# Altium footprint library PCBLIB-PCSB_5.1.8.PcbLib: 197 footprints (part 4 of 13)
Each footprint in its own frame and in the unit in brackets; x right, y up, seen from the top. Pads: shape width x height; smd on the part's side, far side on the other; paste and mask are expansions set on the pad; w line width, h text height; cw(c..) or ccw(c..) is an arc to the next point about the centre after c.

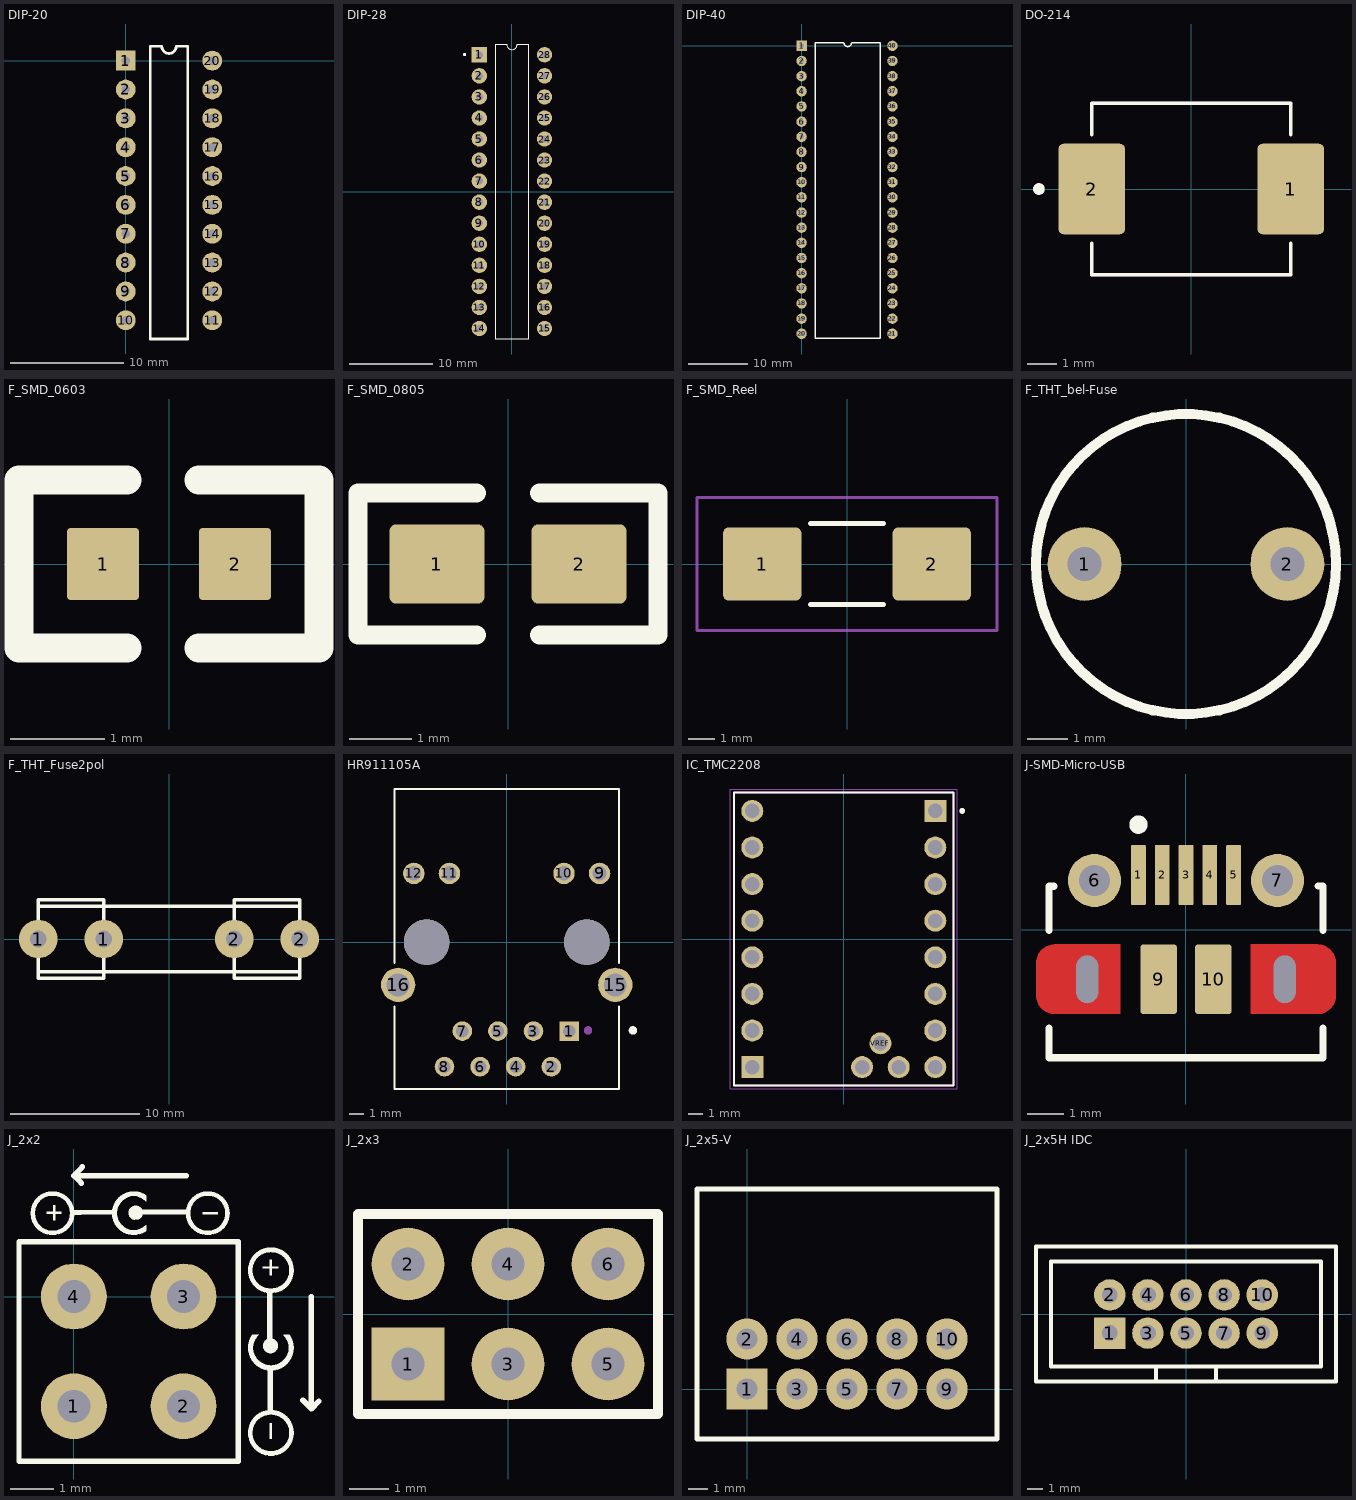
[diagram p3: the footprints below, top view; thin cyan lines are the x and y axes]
## DIP-20 [mm] "LB-2024-04-17"
pads (20):
  rect 1.75x1.75 hole 0.75: 1(0,0)
  round 1.75 hole 0.75: 2(0,-2.54) 3(0,-5.08) 4(0,-7.62) 5(0,-10.16) 6(0,-12.7) 7(0,-15.24) 8(0,-17.78) 9(0,-20.32) 10(0,-22.86) 11(7.62,-22.86) 12(7.62,-20.32) 13(7.62,-17.78) 14(7.62,-15.24) 15(7.62,-12.7) 16(7.62,-10.16) 17(7.62,-7.62) 18(7.62,-5.08) 19(7.62,-2.54) 20(7.62,0)
Top Overlay:
  lines w0.254: 2.159,-24.511 2.159,1.27 3.175,1.27 ccw(c3.81,1.27) 4.445,1.27 5.461,1.27 5.461,-24.511 2.159,-24.511

## DIP-28 [mm] "LB-2024-04-17"
pads (28):
  rect 1.85x1.85 hole 0.85: 1(-3.935,16.51)
  round 1.85 hole 0.85: 2(-3.935,13.97) 3(-3.935,11.43) 4(-3.935,8.89) 5(-3.935,6.35) 6(-3.935,3.81) 7(-3.935,1.27) 8(-3.935,-1.27) 9(-3.935,-3.81) 10(-3.935,-6.35) 11(-3.935,-8.89) 12(-3.935,-11.43) 13(-3.935,-13.97) 14(-3.935,-16.51) 15(3.935,-16.51) 16(3.935,-13.97) 17(3.935,-11.43) 18(3.935,-8.89) 19(3.935,-6.35) 20(3.935,-3.81) 21(3.935,-1.27) 22(3.935,1.27) 23(3.935,3.81) 24(3.935,6.35) 25(3.935,8.89) 26(3.935,11.43) 27(3.935,13.97) 28(3.935,16.51)
Top Overlay:
  circle w0.2: c-5.714,16.544 r0.1
  lines w0.14: -0.66,17.78 -1,17.78 -2,17.78 -2,-17.78 2,-17.78 2,17.78 ; -0.635,17.78 ccw(c0,17.78) 0.635,17.78 ; 0.642,17.78 1.642,17.78 1.981,17.78
Mechanical 13:
  circle w0.2: c-5.714,16.544 r0.1

## DIP-40 [mm] "LB-2024-04-17"
pads (40):
  rect 1.75x1.75 hole 0.75: 1(0,0)
  round 1.75 hole 0.75: 2(0,-2.54) 3(0,-5.08) 4(0,-7.62) 5(0,-10.16) 6(0,-12.7) 7(0,-15.24) 8(0,-17.78) 9(0,-20.32) 10(0,-22.86) 11(0,-25.4) 12(0,-27.94) 13(0,-30.48) 14(0,-33.02) 15(0,-35.56) 16(0,-38.1) 17(0,-40.64) 18(0,-43.18) 19(0,-45.72) 20(0,-48.26) 21(15.24,-48.26) 22(15.24,-45.72) 23(15.24,-43.18) 24(15.24,-40.64) 25(15.24,-38.1) 26(15.24,-35.56) 27(15.24,-33.02) 28(15.24,-30.48) 29(15.24,-27.94) 30(15.24,-25.4) 31(15.24,-22.86) 32(15.24,-20.32) 33(15.24,-17.78) 34(15.24,-15.24) 35(15.24,-12.7) 36(15.24,-10.16) 37(15.24,-7.62) 38(15.24,-5.08) 39(15.24,-2.54) 40(15.24,0)
Top Overlay:
  lines w0.254: 2.286,-49.022 13.208,-49.022 13.208,0.508 8.382,0.508 cw(c7.747,0.508) 7.112,0.508 2.286,0.508 2.286,-49.022

## DO-214 [mm] "LB-2024-09-01"
pads (2):
  rrect15% 2.29x3.12 smd paste-0.02 mask+0.05: 1(3.43,0) 2(-3.43,0)
Top Overlay:
  circle w0.2: c-5.25,0 r0.1
  lines w0.127: -3.427,-1.88 -3.427,-2.953 3.427,-2.953 3.427,-1.88 ; -3.427,1.88 -3.427,2.953 3.427,2.953 3.427,1.88
Mechanical 13:
  circle w0.2: c-5.25,0 r0.1
  lines w0.127: -3.427,-2.953 3.427,-2.953 ; -3.427,2.953 3.427,2.953

## F_SMD_0603 [mil] "LB-2024-04-17"
pads (2):
  rrect10% 30x30 smd paste-0.79 mask+1.97: 1(-27.5,0) 2(27.5,0)
Top Overlay:
  lines w12: -17.5,-35 -62.5,-35 -62.5,35 -17.5,35 ; 12.5,-35 62.5,-35 62.5,35 12.5,35

## F_SMD_0805 [mil] "LB-2024-04-17"
pads (2):
  rrect15% 60x50 smd paste-0.79 mask+1.97: 1(-45,0) 2(45,0)
Top Overlay:
  lines w12: -20,-45 -95,-45 -95,45 -20,45 ; 20,-45 95,-45 95,45 20,45

## F_SMD_Reel [mm] "LB-2024-09-01"
height 2.6
pads (2):
  rrect15% 3x2.8 smd paste-0.02 mask+0.05: 1(-3.25,0) 2(3.25,0)
Top Overlay:
  lines w0.2: -1.4,-1.55 1.4,-1.55 ; -1.4,1.55 1.4,1.55
Mechanical 20:
  lines w0.1: -5.75,-2.55 5.75,-2.55 5.75,2.55 -5.75,2.55 -5.75,-2.55

## F_THT_bel-Fuse [mm]
pads (2):
  round 1.85 hole 0.85: 1(-2.54,0) 2(2.54,0)
Top Overlay:
  circle w0.254: c0,0 r3.758

## F_THT_Fuse2pol [mm] "LB-2024-04-17"
pads (4):
  round 3 hole 1.3: 1(-10.163,0.008) 1(-5.083,0.008) 2(5.077,0.008) 2(10.157,0.008)
Top Overlay:
  lines w0.254: -10.163,-2.532 -10.163,-3.04 -5.083,-3.04 -5.083,-2.532 -5.083,2.548 -5.083,3.056 -10.163,3.056 -10.163,2.548 ; -10.163,-2.532 10.157,-2.532 ; -10.163,-2.532 -10.163,2.548 ; -10.163,2.548 10.157,2.548 ; 10.157,-2.532 10.157,-3.04 5.077,-3.04 5.077,-2.532 5.077,2.548 5.077,3.056 10.157,3.056 10.157,2.548 ; 10.157,-2.532 10.157,2.548

## HR911105A [mm] "LB-2024-12-26"
pads (16):
  rect 1.398x1.398 / inner round 1.398 / far side rect 1.398x1.398 hole 0.89: 1(4.45,-6.35)
  round 1.398 hole 0.89: 2(3.18,-8.89) 3(1.91,-6.35) 4(0.64,-8.89) 5(-0.63,-6.35) 6(-1.9,-8.89) 7(-3.17,-6.35) 8(-4.44,-8.89)
  round 1.53 hole 1.02: 9(6.625,4.9) 10(4.085,4.9) 11(-4.085,4.9) 12(-6.625,4.9)
  round 2.445 hole 1.63: 15(7.745,-3.05) 16(-7.745,-3.05)
  round 3.25 hole 3.25 unplated: ""(-5.715,0) ""(5.715,0)
Top Overlay:
  circle w0.3: c9,-6.3 r0.15
  lines w0.127: -8,-4.6 -8,-10.48 8,-10.48 8,-4.6 ; -8,-1.5 -8,10.92 8,10.92 8,-1.5
Mechanical 13:
  circle w0.3: c5.8,-6.3 r0.15

## IC_TMC2208 [mil] "LB-24-10-23"
pads (19):
  rect 60x60 hole 40: JP1_1(250,350) JP2_1(-250,-350)
  round 60 hole 40: JP1_2(250,250) JP1_3(250,150) JP1_4(250,50) JP1_5(250,-50) JP1_6(250,-150) JP1_7(250,-250) JP1_8(250,-350) JP2_2(-250,-250) JP2_3(-250,-150) JP2_4(-250,-50) JP2_5(-250,50) JP2_6(-250,150) JP2_7(-250,250) JP2_8(-250,350) JP3_1(50,-350) JP3_2(150,-350) VREF(100,-285)
Top Overlay:
  circle w7.87: c323.23,350 r3.94
  lines w5: -300,-400 -300,400 300,400 300,-400 -300,-400
Mechanical 13:
  circle w7.87: c323.23,350 r3.94
  lines w5: -300,-400 -300,400 300,400 300,-400 -300,-400
Mechanical 15:
  lines w1.97: -309.84,-409.84 309.84,-409.84 309.84,409.84 -309.84,409.84 -309.84,-409.84

## J-SMD-Micro-USB [mm] "LB-2024-04-18"
height 2.673
pads (11):
  rrect15% 0.4x1.65 smd paste-0.02 mask+0.05: 1(-1.3,1.5) 2(-0.65,1.5) 3(0,1.5) 4(0.65,1.5) 5(1.3,1.5)
  round 1.45 hole 0.85: 6(-2.5,1.35) 7(2.5,1.35)
  rrect50% 0x0 hole 0.6 slot 1.3 at 90 deg: 8(-2.7,-1.35) 11(2.7,-1.35)
  rrect15% 1x1.9 smd paste-0.02 mask+0.05: 9(-0.75,-1.35) 10(0.75,-1.35)
Top Layer:
  circle w0.5: c3.6,-0.9 r0.25
  circle w0.5: c3.6,-1.8 r0.25
  circle w0.5: c-3.6,-0.9 r0.25
  circle w0.5: c-3.6,-1.8 r0.25
  region: 3.6,-0.9 3.6,-1.8 4.1,-1.8 4.1,-0.9
  region: 1.775,-0.4 1.775,-2.3 3.6,-2.3 3.6,-0.4
  region: -3.6,-1.8 -3.6,-0.9 -4.1,-0.9 -4.1,-1.8
  region: -1.8,-2.3 -1.8,-0.4 -3.6,-0.4 -3.6,-2.3
Top Overlay:
  circle w0.25: c-1.3,2.875 r0.125
  lines w0.2: -3.745,-2.688 -3.745,-3.5 3.745,-3.5 3.745,-2.688 ; -3.745,-0.012 -3.745,1.195 -3.614,1.195 ; 3.615,1.2 3.745,1.2 3.745,-0.012

## J_2x2 [mil] "LB-2024-05-28"
pads (4):
  round 60 hole 30: 1(0,-100) 2(100,-100) 3(100,0) 4(0,0)
Top Overlay:
  drawing of 20 lines, arcs and shapes, not listed

## J_2x3 [mm] "LB-2024-04-19"
pads (6):
  rect 1.85x1.85 hole 0.85 mask+0.102: 1(-2.54,-1.27)
  round 1.85 hole 0.85 mask+0.102: 2(-2.54,1.27) 3(0,-1.27) 4(0,1.27) 5(2.54,-1.27) 6(2.54,1.27)
Top Overlay:
  lines w0.254: -3.81,-2.54 -3.81,2.54 3.81,2.54 3.81,-2.54 -3.81,-2.54

## J_2x5-V [mm] "LB-2024-04-19"
height 9
pads (10):
  rect 2.1x2.1 hole 1.05 mask+0.102: 1(0,0)
  round 2.1 hole 1.05 mask+0.102: 2(0,2.54) 3(2.54,0) 4(2.54,2.54) 5(5.08,0) 6(5.08,2.54) 7(7.62,0) 8(7.62,2.54) 9(10.16,0) 10(10.16,2.54)
Top Overlay:
  lines w0.254: -2.54,-2.54 -2.54,10.16 12.7,10.16 12.7,7.62 12.7,-2.54 -2.54,-2.54

## J_2x5H IDC [mm] "LB-2024-04-19"
height 9
pads (10):
  rect 2.1x2.1 hole 1.05 mask+0.102: 1(-5.08,-1.27)
  round 2.1 hole 1.05 mask+0.102: 2(-5.08,1.27) 3(-2.54,-1.27) 4(-2.54,1.27) 5(0,-1.27) 6(0,1.27) 7(2.54,-1.27) 8(2.54,1.27) 9(5.08,-1.27) 10(5.08,1.27)
Top Overlay:
  lines w0.254: -2,-4.5 -2,-3.5 ; -0.5,4.5 10,4.5 10,-4.5 -10,-4.5 -10,4.5 0,4.5 ; 2,-4.5 2,-3.5 ; -9,-3.5 9,-3.5 9,3.5 -9,3.5 -9,-3.5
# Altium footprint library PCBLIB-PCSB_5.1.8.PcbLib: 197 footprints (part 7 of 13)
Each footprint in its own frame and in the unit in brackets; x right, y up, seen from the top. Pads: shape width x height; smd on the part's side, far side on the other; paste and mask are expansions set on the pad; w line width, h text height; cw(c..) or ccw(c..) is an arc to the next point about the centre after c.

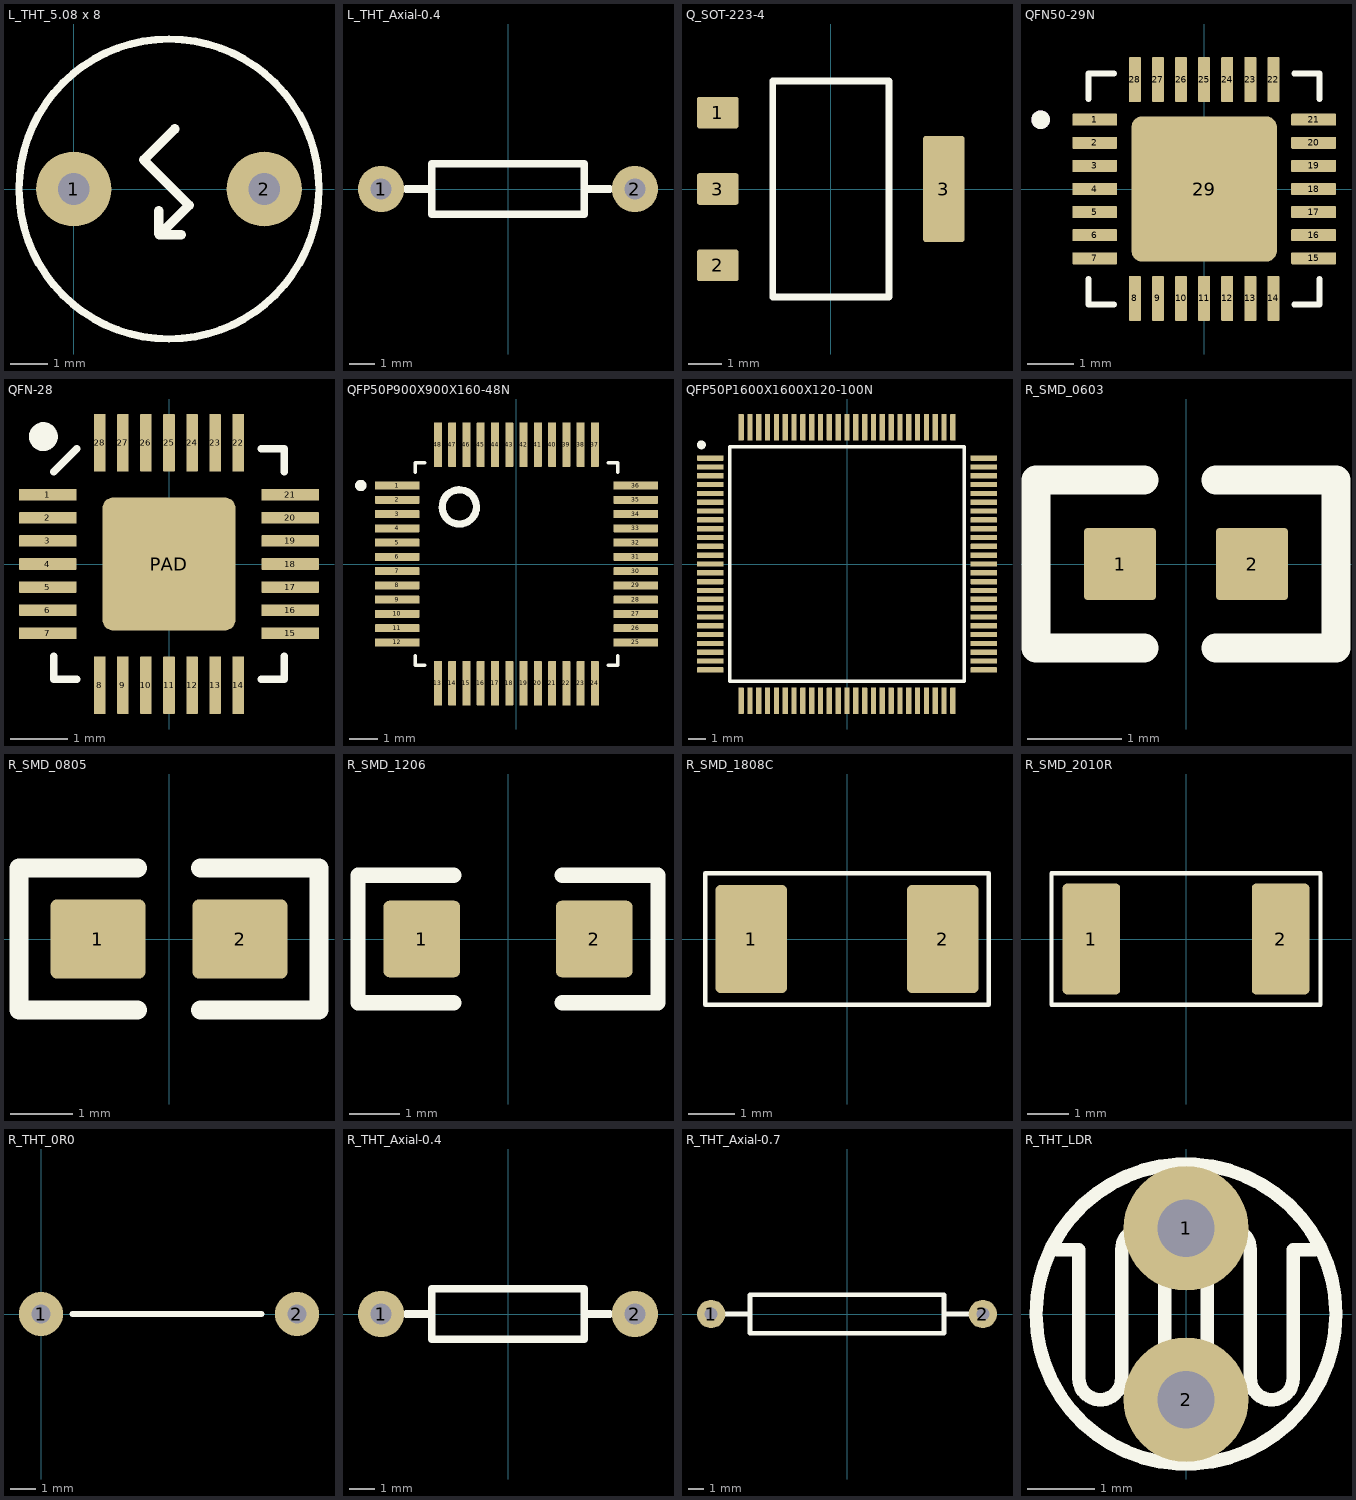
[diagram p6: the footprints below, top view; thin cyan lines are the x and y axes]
## L_THT_5.08 x 8 [mm] "LB-2024-04-17"
pads (2):
  round 2 hole 0.85: 1(0,0) 2(5.08,0)
Top Overlay:
  circle w0.2: c2.54,0 r4
  lines w0.254: 2.261,-0.762 2.261,-1.194 ; 2.261,-0.584 2.261,-1.194 ; 2.692,1.6 1.867,0.775 3.073,-0.432 2.286,-1.219 ; 2.261,-1.194 2.286,-1.219 ; 2.286,-1.219 2.87,-1.219 ; 2.286,-1.219 2.87,-1.219 ; 2.286,-1.219 2.87,-1.219

## L_THT_Axial-0.4 [mm]
pads (2):
  round 1.85 hole 0.85: 1(-5.08,0) 2(5.08,0)
Top Overlay:
  lines w0.305: -4.064,0 -3.048,0 ; 3.048,0 4.064,0 ; -3.048,-1.016 3.048,-1.016 3.048,1.016 -3.048,1.016 -3.048,-1.016

## Q_SOT-223-4 [mm] "LB-2025-01-10"
pads (4):
  rrect15% 1.25x0.95 smd paste-0.02 mask+0.05: 1(-3.4,2.3) 2(-3.4,-2.3) 3(-3.4,0)
  rrect15% 1.25x3.2 smd paste-0.02 mask+0.05: 3(3.4,0)
Top Overlay:
  lines w0.2: -1.75,-3.25 1.75,-3.25 1.75,3.25 -1.75,3.25 -1.75,-3.25

## QFN50-29N [mm] "LB-2024-09-01"
pads (29):
  rrect15% 0.97x0.26 smd paste-0.02 mask+0.05: 1(-2.37,1.5) 2(-2.37,1) 3(-2.37,0.5) 4(-2.37,0) 5(-2.37,-0.5) 6(-2.37,-1) 7(-2.37,-1.5) 15(2.37,-1.5) 16(2.37,-1) 17(2.37,-0.5) 18(2.37,0) 19(2.37,0.5) 20(2.37,1) 21(2.37,1.5)
  rrect15% 0.26x0.97 smd paste-0.02 mask+0.05: 8(-1.5,-2.37) 9(-1,-2.37) 10(-0.5,-2.37) 11(0,-2.37) 12(0.5,-2.37) 13(1,-2.37) 14(1.5,-2.37) 22(1.5,2.37) 23(1,2.37) 24(0.5,2.37) 25(0,2.37) 26(-0.5,2.37) 27(-1,2.37) 28(-1.5,2.37)
  rrect15% 3.15x3.15 smd paste-0.02 mask+0.05: 29(0,0)
Top Overlay:
  circle w0.2: c-3.54,1.5 r0.1
  lines w0.127: -2.5,-1.95 -2.5,-2.5 -1.95,-2.5 ; -2.5,1.95 -2.5,2.5 -1.95,2.5 ; 1.95,-2.5 2.5,-2.5 2.5,-1.95 ; 1.95,2.5 2.5,2.5 2.5,1.95
Mechanical 13:
  circle w0.2: c-3.54,1.5 r0.1

## QFN-28 [mm] "LB-2024-09-01"
pads (29):
  rrect15% 1x0.2 smd paste-0.02 mask+0.05: 1(-2.1,1.2) 2(-2.1,0.8) 3(-2.1,0.4) 4(-2.1,0) 5(-2.1,-0.4) 6(-2.1,-0.8) 7(-2.1,-1.2) 15(2.1,-1.2) 16(2.1,-0.8) 17(2.1,-0.4) 18(2.1,0) 19(2.1,0.4) 20(2.1,0.8) 21(2.1,1.2)
  rrect15% 0.2x1 smd paste-0.02 mask+0.05: 8(-1.2,-2.1) 9(-0.8,-2.1) 10(-0.4,-2.1) 11(0,-2.1) 12(0.4,-2.1) 13(0.8,-2.1) 14(1.2,-2.1) 22(1.2,2.1) 23(0.8,2.1) 24(0.4,2.1) 25(0,2.1) 26(-0.4,2.1) 27(-0.8,2.1) 28(-1.2,2.1)
  rrect15% 2.3x2.3 smd paste-0.02 mask+0.05: PAD(0,0)
Top Overlay:
  circle w0.3: c-2.178,2.208 r0.1
  lines w0.127: -2,-1.6 -2,-2 -1.6,-2 ; -2,1.6 -1.6,2 ; 1.6,-2 2,-2 2,-1.6 ; 1.6,2 2,2 2,1.6
Top Paste:
  region: -0.9,0.9 -0.4,0.9 -0.4,0.4 -0.9,0.4
  region: 0.4,0.9 0.9,0.9 0.9,0.4 0.4,0.4
  region: 0.4,-0.4 0.9,-0.4 0.9,-0.9 0.4,-0.9
  region: -0.9,-0.4 -0.4,-0.4 -0.4,-0.9 -0.9,-0.9

## QFP50P900X900X160-48N [mm] "LB-2025-01-10"
pads (48):
  rrect15% 1.56x0.28 smd paste-0.02 mask+0.05: 1(-4.18,2.75) 2(-4.18,2.25) 3(-4.18,1.75) 4(-4.18,1.25) 5(-4.18,0.75) 6(-4.18,0.25) 7(-4.18,-0.25) 8(-4.18,-0.75) 9(-4.18,-1.25) 10(-4.18,-1.75) 11(-4.18,-2.25) 12(-4.18,-2.75) 25(4.18,-2.75) 26(4.18,-2.25) 27(4.18,-1.75) 28(4.18,-1.25) 29(4.18,-0.75) 30(4.18,-0.25) 31(4.18,0.25) 32(4.18,0.75) 33(4.18,1.25) 34(4.18,1.75) 35(4.18,2.25) 36(4.18,2.75)
  rrect15% 0.28x1.56 smd paste-0.02 mask+0.05: 13(-2.75,-4.18) 14(-2.25,-4.18) 15(-1.75,-4.18) 16(-1.25,-4.18) 17(-0.75,-4.18) 18(-0.25,-4.18) 19(0.25,-4.18) 20(0.75,-4.18) 21(1.25,-4.18) 22(1.75,-4.18) 23(2.25,-4.18) 24(2.75,-4.18) 37(2.75,4.18) 38(2.25,4.18) 39(1.75,4.18) 40(1.25,4.18) 41(0.75,4.18) 42(0.25,4.18) 43(-0.25,4.18) 44(-0.75,4.18) 45(-1.25,4.18) 46(-1.75,4.18) 47(-2.25,4.18) 48(-2.75,4.18)
Top Overlay:
  circle w0.2: c-5.45,2.75 r0.1
  lines w0.127: -3.55,-3.22 -3.55,-3.55 -3.22,-3.55 ; -3.55,3.22 -3.55,3.55 -3.22,3.55 ; 3.22,-3.55 3.55,-3.55 3.55,-3.22 ; 3.22,3.55 3.55,3.55 3.55,3.22
  lines w0.254: -1.401,2.032 ccw(c-2,2) -1.4,2

## QFP50P1600X1600X120-100N [mm]
pads (100):
  rrect15% 1.5x0.3 smd paste-0.02 mask+0.05: 1(-7.75,6) 2(-7.75,5.5) 3(-7.75,5) 4(-7.75,4.5) 5(-7.75,4) 6(-7.75,3.5) 7(-7.75,3) 8(-7.75,2.5) 9(-7.75,2) 10(-7.75,1.5) 11(-7.75,1) 12(-7.75,0.5) 13(-7.75,0) 14(-7.75,-0.5) 15(-7.75,-1) 16(-7.75,-1.5) 17(-7.75,-2) 18(-7.75,-2.5) 19(-7.75,-3) 20(-7.75,-3.5) 21(-7.75,-4) 22(-7.75,-4.5) 23(-7.75,-5) 24(-7.75,-5.5) 25(-7.75,-6) 51(7.75,-6) 52(7.75,-5.5) 53(7.75,-5) 54(7.75,-4.5) 55(7.75,-4) 56(7.75,-3.5) 57(7.75,-3) 58(7.75,-2.5) 59(7.75,-2) 60(7.75,-1.5) 61(7.75,-1) 62(7.75,-0.5) 63(7.75,0) 64(7.75,0.5) 65(7.75,1) 66(7.75,1.5) 67(7.75,2) 68(7.75,2.5) 69(7.75,3) 70(7.75,3.5) 71(7.75,4) 72(7.75,4.5) 73(7.75,5) 74(7.75,5.5) 75(7.75,6)
  rrect15% 0.3x1.5 smd paste-0.02 mask+0.05: 26(-6,-7.75) 27(-5.5,-7.75) 28(-5,-7.75) 29(-4.5,-7.75) 30(-4,-7.75) 31(-3.5,-7.75) 32(-3,-7.75) 33(-2.5,-7.75) 34(-2,-7.75) 35(-1.5,-7.75) 36(-1,-7.75) 37(-0.5,-7.75) 38(0,-7.75) 39(0.5,-7.75) 40(1,-7.75) 41(1.5,-7.75) 42(2,-7.75) 43(2.5,-7.75) 44(3,-7.75) 45(3.5,-7.75) 46(4,-7.75) 47(4.5,-7.75) 48(5,-7.75) 49(5.5,-7.75) 50(6,-7.75) 76(6,7.75) 77(5.5,7.75) 78(5,7.75) 79(4.5,7.75) 80(4,7.75) 81(3.5,7.75) 82(3,7.75) 83(2.5,7.75) 84(2,7.75) 85(1.5,7.75) 86(1,7.75) 87(0.5,7.75) 88(0,7.75) 89(-0.5,7.75) 90(-1,7.75) 91(-1.5,7.75) 92(-2,7.75) 93(-2.5,7.75) 94(-3,7.75) 95(-3.5,7.75) 96(-4,7.75) 97(-4.5,7.75) 98(-5,7.75) 99(-5.5,7.75) 100(-6,7.75)
Top Overlay:
  circle w0.25: c-8.25,6.75 r0.125
  lines w0.2: -6.65,-6.65 6.65,-6.65 6.65,6.65 -6.65,6.65 -6.65,-6.65

## R_SMD_0603 [mil] "LB-2024-04-17"
pads (2):
  rrect10% 30x30 smd paste-0.79 mask+1.97: 1(-27.5,0) 2(27.5,0)
Top Overlay:
  lines w12: -17.5,-35 -62.5,-35 -62.5,35 -17.5,35 ; 12.5,-35 62.5,-35 62.5,35 12.5,35

## R_SMD_0805 [mil] "LB-2024-04-17"
pads (2):
  rrect15% 60x50 smd paste-0.79 mask+1.97: 1(-45,0) 2(45,0)
Top Overlay:
  lines w12: -20,-45 -95,-45 -95,45 -20,45 ; 20,-45 95,-45 95,45 20,45

## R_SMD_1206 [mil] "LB-2024-04-17"
pads (2):
  rrect15% 60x60 smd paste-0.79 mask+1.97: 1(-67.5,0) 2(67.5,0)
Top Overlay:
  lines w12: -42.5,-50 -117.5,-50 -117.5,50 -42.5,50 ; 42.5,-50 117.5,-50 117.5,50 42.5,50

## R_SMD_1808C [mm] "LB-2024-04-17"
height 2
pads (2):
  rrect15% 1.55x2.35 smd paste-0.02 mask+0.05: 1(-2.075,0) 2(2.075,0)
Top Overlay:
  lines w0.1: -3.075,-1.425 -3.075,1.425 3.075,1.425 3.075,-1.425 -3.075,-1.425

## R_SMD_2010R [mm] "LB-2024-04-17"
height 0.7
pads (2):
  rrect15% 1.4x2.7 smd paste-0.02 mask+0.05: 1(-2.3,0) 2(2.3,0)
Top Overlay:
  lines w0.1: -3.275,-1.6 3.275,-1.6 3.275,1.6 -3.275,1.6 -3.275,-1.6

## R_THT_0R0 [mm] "LB-2024-08-13"
pads (2):
  round 1.75 hole 0.75: 1(0,0) 2(10.16,0)
Top Overlay:
  lines w0.254: 1.25,0 8.75,0

## R_THT_Axial-0.4 [mm] "LB-2024-04-17"
pads (2):
  round 1.85 hole 0.85: 1(-5.08,0) 2(5.08,0)
Top Overlay:
  lines w0.305: -4.064,0 -3.048,0 ; 3.048,0 4.064,0 ; -3.048,-1.016 3.048,-1.016 3.048,1.016 -3.048,1.016 -3.048,-1.016

## R_THT_Axial-0.7 [mm] "LB-2024-04-17"
pads (2):
  round 1.85 hole 0.85: 1(-8.89,0) 2(8.89,0)
Top Overlay:
  lines w0.305: -8.89,0 -6.35,0 ; 6.35,0 8.89,0 ; -6.35,-1.27 -6.35,1.27 6.35,1.27 6.35,-1.27 -6.35,-1.27

## R_THT_LDR [mm] "LB-2024-04-18"
pads (2):
  round 1.85 hole 0.85: 1(0,1.27) 2(0,-1.27)
Top Overlay:
  circle w0.2: c0,0 r2.222
  lines w0.2: -1.905,0.953 -1.587,0.953 -1.587,-0.953 ccw(c-1.27,-0.953) -0.953,-0.953 -0.953,0.953 cw(c-0.635,0.953) -0.318,0.953 -0.318,-0.953 ; 0.318,-0.953 0.318,0.953 cw(c0.635,0.953) 0.953,0.953 0.953,-0.953 ccw(c1.27,-0.953) 1.587,-0.953 1.587,0.953 1.905,0.953
Mechanical 13:
  lines w0.2: -0.318,-0.953 ccw(c0,-0.953) 0.318,-0.953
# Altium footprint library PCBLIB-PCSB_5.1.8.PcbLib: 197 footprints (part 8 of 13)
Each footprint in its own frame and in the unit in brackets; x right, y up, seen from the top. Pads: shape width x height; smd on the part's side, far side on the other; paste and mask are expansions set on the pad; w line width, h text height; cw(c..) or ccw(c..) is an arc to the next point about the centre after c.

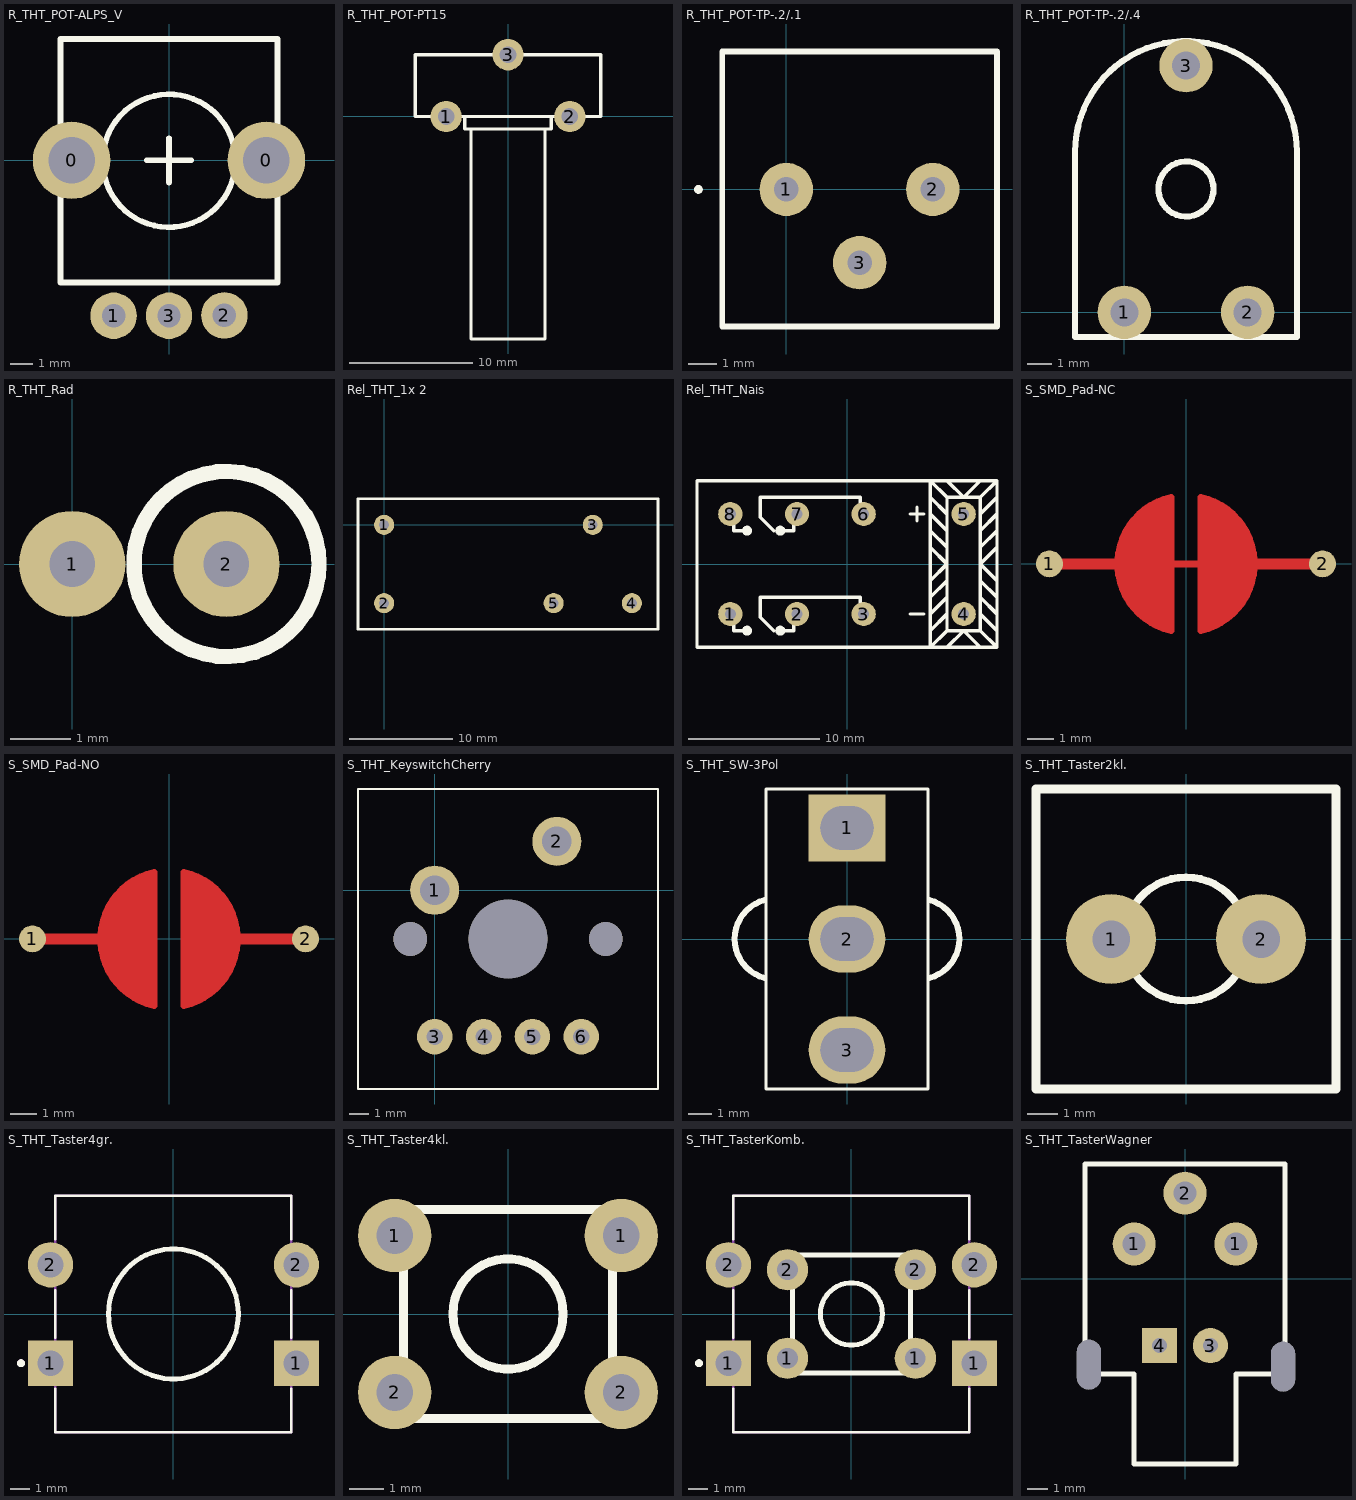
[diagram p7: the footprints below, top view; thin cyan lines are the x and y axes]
## R_THT_POT-ALPS_V [mm]
height 15
pads (5):
  round 3.5 hole 2.1: 0(-4.4,0) 0(4.4,0)
  round 2.1 hole 1.05: 1(-2.5,-7.02) 2(2.5,-7) 3(0,-7.02)
Top Overlay:
  circle w0.254: c0,-0.02 r3
  lines w0.254: -1,0 1,0 ; 0,-1 0,0 0,1 ; -4.9,-5.52 -4.9,5.48 4.9,5.48 4.9,-5.52 -4.9,-5.52

## R_THT_POT-PT15 [mm] "LB-2024-04-17"
pads (3):
  round 2.54 hole 1.35: 1(-5.006,-0.011) 2(4.994,-0.011) 3(-0.006,4.989)
Top Overlay:
  lines w0.254: -3.506,-0.011 -3.506,-1.011 3.494,-1.011 3.494,-0.011 ; -3,-1.011 -3,-18 3,-18 3,-1.011 ; -7.506,-0.011 -7.506,4.989 7.494,4.989 7.494,-0.011 -7.506,-0.011

## R_THT_POT-TP-.2/.1 [mm] "LB-2024-12-11"
pads (3):
  round 1.85 hole 0.85: 1(0,0) 2(5.08,0) 3(2.54,-2.54)
Top Overlay:
  lines w0.2: -3.1,0 cw(c-3.05,0) -3,0 ; -3.1,0 ccw(c-3.05,0) -3,0 ; -3.1,0 cw(c-3.05,0) -3,0 ; -2.225,-4.75 -2.225,4.78 7.305,4.78 7.305,-4.75 -2.225,-4.75

## R_THT_POT-TP-.2/.4 [mm] "LB-2024-04-17"
pads (3):
  round 2.2 hole 1.15: 1(0,0) 2(5.08,0) 3(2.54,10.16)
Top Overlay:
  circle w0.254: c2.54,5.08 r1.136
  lines w0.254: -2.032,-1.016 7.112,-1.016 7.112,6.604 ccw(c2.54,6.604) -2.032,6.604 -2.032,-1.016

## R_THT_Rad [mm] "LB-2024-04-17"
pads (2):
  round 1.75 hole 0.75: 1(0,0) 2(2.54,0)
Top Overlay:
  circle w0.254: c2.54,0 r1.524

## Rel_THT_1x 2 [mm] "LB-2024-04-18"
pads (5):
  round 1.95 hole 0.95: 1(0,0) 2(0,-7.62) 3(20.32,0) 4(24.13,-7.62) 5(16.51,-7.62)
Top Overlay:
  lines w0.254: -2.54,-10.16 -2.54,2.54 26.67,2.54 26.67,-10.16 -2.54,-10.16

## Rel_THT_Nais [mm] "LB-2024-04-17"
pads (8):
  round 1.85 hole 0.85: 1(-8.89,-3.81) 2(-3.81,-3.81) 3(1.27,-3.81) 4(8.89,-3.81) 5(8.89,3.81) 6(1.27,3.81) 7(-3.81,3.81) 8(-8.89,3.81)
Top Overlay:
  circle w0.254: c-5.08,2.54 r0.254
  circle w0.254: c-7.62,2.54 r0.254
  circle w0.254: c-5.08,-5.08 r0.254
  circle w0.254: c-7.62,-5.08 r0.254
  region: -7.366,2.54 -7.62,2.54 -7.595,2.515 -7.595,2.286 -7.62,2.286 -7.671,2.337 -7.62,2.388 -7.62,2.591 -7.493,2.464 -7.493,2.337
  region: -7.772,2.769 -7.747,2.743 -7.442,2.743 -7.442,2.388 -7.493,2.337 -7.671,2.337 -7.671,2.616 -7.798,2.743
  region: -5.232,2.769 -4.877,2.769 -4.877,2.362 -4.928,2.311 -5.258,2.311 -5.258,2.743
  region: -5.334,-4.826 -4.826,-4.826 -4.826,-5.334 -5.334,-5.334
  region: -7.874,-4.826 -7.366,-4.826 -7.366,-5.334 -7.874,-5.334
  lines w0.254: -8.636,-4.572 -8.636,-5.08 -7.62,-5.08 ; -8.636,3.048 -8.636,2.54 -7.62,2.54 ; -5.588,-5.08 -6.604,-4.064 -6.604,-3.048 -6.604,-2.54 1.016,-2.54 1.016,-3.048 ; -5.588,2.54 -6.604,3.556 -6.604,4.572 -6.604,5.08 1.016,5.08 1.016,4.572 ; -5.08,-5.08 -4.064,-5.08 -4.064,-4.572 ; -5.08,2.54 -4.064,2.54 -4.064,3.048 ; 4.826,-3.81 5.842,-3.81 ; 4.826,3.81 5.842,3.81 ; 5.334,3.302 5.334,4.318 ; 7.62,-3.81 6.35,-5.08 6.35,-3.81 7.62,-2.54 7.62,-1.27 6.35,-2.54 6.35,-1.27 7.62,0 6.35,1.27 6.35,2.54 7.62,1.27 7.62,2.54 6.35,3.81 6.35,5.08 7.62,3.81 ; 10.16,-6.35 8.89,-5.08 7.62,-6.35 6.35,-6.35 ; 10.16,3.81 11.43,5.08 11.43,3.81 10.16,2.54 10.16,1.27 11.43,2.54 11.43,1.27 10.16,0 ; 10.16,6.35 8.89,5.08 7.62,6.35 6.35,6.35 ; 11.43,0 11.43,-1.27 ; 6.35,-6.35 6.35,6.35 ; 6.35,-6.35 7.62,-5.08 ; 6.35,6.35 7.62,5.08 ; 7.62,-5.08 7.62,5.08 ; 7.62,-5.08 10.16,-5.08 ; 7.62,5.08 10.16,5.08 ; 10.16,-5.08 11.43,-6.35 ; 10.16,-5.08 10.16,5.08 ; 10.16,0 10.16,-1.27 11.43,-2.54 11.43,-1.27 ; 10.16,0 11.43,-1.27 ; 10.16,5.08 11.43,6.35 ; 11.43,-6.35 -11.43,-6.35 -11.43,6.35 11.43,6.35 ; 11.43,-6.35 11.43,6.35 ; 10.16,-3.81 10.16,-2.54 11.43,-3.81 11.43,-5.08 10.16,-3.81

## S_SMD_Pad-NC [mm] "LB-2024-04-18"
pads (2):
  round 1 smd: 1(-5.08,0) 2(5.08,0)
Top Layer:
  region: -0.551,-2.48 -0.551,2.48 -0.618,2.413 -1.016,2.413 -1.524,1.905 -1.651,1.905 -2.159,1.397 -2.159,1.143 -2.54,0.762 -2.54,-0.762 -2.159,-1.143 -2.159,-1.397 -1.27,-2.286 -1.016,-2.286 -0.762,-2.54 -0.702,-2.48
  region: 0.551,2.48 0.551,-2.48 0.618,-2.413 1.016,-2.413 1.524,-1.905 1.651,-1.905 2.159,-1.397 2.159,-1.143 2.54,-0.762 2.54,0.762 2.159,1.143 2.159,1.397 1.27,2.286 1.016,2.286 0.762,2.54 0.702,2.48
  lines w0.254: -0.762,0 0.762,0 ; -0.551,-2.48 cw(c0,0) -0.551,2.48 -0.551,-2.48 ; 0.551,-2.48 ccw(c0,0) 0.551,2.48 0.551,-2.48
  lines w0.4: -5.08,0 -2.032,0 ; 2.032,0 5.08,0
Top Solder:
  circle w0.3: c0,0 r2.736
  region: -0.813,2.667 -0.762,2.718 0.838,2.718 1.27,2.286 1.549,2.286 2.54,1.295 2.54,0.635 2.794,0.381 2.736,0.323 2.736,-0.566 2.54,-0.762 2.616,-0.838 2.616,-1.143 2.21,-1.549 2.21,-1.702 2.184,-1.702 1.422,-2.464 1.067,-2.464 0.838,-2.692 -0.533,-2.692 -0.584,-2.743 -0.762,-2.565 -0.762,-2.54 -1.245,-2.54 -1.676,-2.108 -1.778,-2.108 -2.388,-1.499 -2.388,-1.346 -2.54,-1.194 -2.54,-0.737 -2.736,-0.541 -2.736,0.439 -2.667,0.508 -2.692,0.533 -2.692,0.94 -2.337,1.295 -2.337,1.6 -2.311,1.6 -1.473,2.438 -1.219,2.438 -1.016,2.642

## S_SMD_Pad-NO [mm] "LB-2024-04-18"
pads (2):
  round 1 smd: 1(-5.08,0) 2(5.08,0)
Top Layer:
  region: -0.551,-2.48 -0.551,2.48 -0.618,2.413 -1.016,2.413 -1.524,1.905 -1.651,1.905 -2.159,1.397 -2.159,1.143 -2.54,0.762 -2.54,-0.762 -2.159,-1.143 -2.159,-1.397 -1.27,-2.286 -1.016,-2.286 -0.762,-2.54 -0.702,-2.48
  region: 0.551,2.48 0.551,-2.48 0.618,-2.413 1.016,-2.413 1.524,-1.905 1.651,-1.905 2.159,-1.397 2.159,-1.143 2.54,-0.762 2.54,0.762 2.159,1.143 2.159,1.397 1.27,2.286 1.016,2.286 0.762,2.54 0.702,2.48
  lines w0.254: -0.551,-2.48 cw(c0,0) -0.551,2.48 -0.551,-2.48 ; 0.551,-2.48 ccw(c0,0) 0.551,2.48 0.551,-2.48
  lines w0.4: -5.08,0 -2.032,0 ; 2.032,0 5.08,0
Top Solder:
  circle w0.3: c0,0 r2.736
  region: -0.914,2.616 -0.838,2.692 1.016,2.616 2.489,1.321 2.489,1.118 2.515,1.118 2.736,0.897 2.736,-0.566 2.54,-0.762 2.565,-0.787 2.565,-1.245 1.829,-1.981 1.829,-2.134 1.651,-2.134 1.252,-2.533 0.693,-2.533 0.483,-2.743 -0.559,-2.743 -0.762,-2.54 -1.016,-2.54 -1.067,-2.591 -1.346,-2.311 -1.549,-2.311 -2.286,-1.575 -2.286,-1.372 -2.743,-0.914 -2.743,-0.008 -2.718,0.018 -2.718,0.838 -2.311,1.245 -2.311,1.626 -1.473,2.464 -1.168,2.464 -0.914,2.718 -0.635,2.718

## S_THT_KeyswitchCherry [mm] "LB-2024-04-18"
pads (9):
  round 2.55 hole 1.55: 1(0,0) 2(6.35,2.54)
  round 1.85 hole 0.85: 3(0,-7.62) 4(2.54,-7.62) 5(5.08,-7.62) 6(7.62,-7.62)
  round 1.753 hole 1.753 unplated: ""(-1.27,-2.54) ""(8.89,-2.54)
  round 4.089 hole 4.089 unplated: ""(3.81,-2.54)
Top Overlay:
  lines w0.127: -3.99,-10.34 11.61,-10.34 11.61,5.26 -3.99,5.26 -3.99,-10.34

## S_THT_SW-3Pol [mm]
pads (3):
  rect 3.25x2.85 hole 1.85 slot 2.25 at 0 deg: 1(0,4.7)
  oval 3.25x2.85 hole 1.85 slot 2.25 at 0 deg: 2(0,0) 3(0,-4.7)
Top Overlay:
  lines w0.127: -1.71,-6.35 -3.43,-6.35 ; -1.71,6.35 -3.43,6.35 ; 1.71,-6.35 3.43,-6.35 ; 1.71,6.35 3.43,6.35 ; -3.43,-6.35 -3.43,6.35 ; -3.43,-6.35 3.43,-6.35 ; -3.43,-6.35 -3.43,6.35 ; -3.43,6.35 3.43,6.35 ; 3.43,-6.35 3.43,6.35 ; 3.43,-6.35 3.43,6.35
  lines w0.254: -3.49,-1.65 cw(c-3.048,0) -3.49,1.65 ; 3.49,-1.65 ccw(c3.048,0) 3.49,1.65

## S_THT_Taster2kl. [mm] "LB-2024-04-17"
height 20
pads (2):
  round 3 hole 1.25 unplated: 1(-2.5,0) 2(2.5,0)
Top Overlay:
  circle w0.254: c0,0 r2.062
  lines w0.3: -5,-5 5,-5 5,5 -5,5 -5,-5

## S_THT_Taster4gr. [mm] "LB-2024-04-17"
height 7.8
pads (4):
  rect 2.3x2.3 hole 1.3: 1(-6.25,-2.5) 1(6.25,-2.5)
  round 2.3 hole 1.3: 2(-6.25,2.5) 2(6.25,2.5)
Top Overlay:
  circle w0.2: c-7.75,-2.5 r0.1
  circle w0.254: c0,0 r3.302
  lines w0.127: -6,-3.788 -6,-6 6,-6 6,-3.788 ; -6,-1.212 -6,1.212 ; -6,3.788 -6,6 6,6 6,3.788 ; 6,-1.212 6,1.212
Mechanical 13:
  circle w0.2: c-7.75,-2.5 r0.1
  lines w0.127: -6,-6 -6,6 6,6 6,-6 -6,-6

## S_THT_Taster4kl. [mm] "LB-2024-04-17"
pads (4):
  round 2.1 hole 1.05: 1(-3.25,2.25) 1(3.25,2.25) 2(-3.25,-2.25) 2(3.25,-2.25)
Top Overlay:
  circle w0.254: c0,0 r1.581
  lines w0.254: -3,-3 3,-3 3,3 -3,3 -3,-3

## S_THT_TasterKomb. [mm] "LB-2024-04-17"
height 7.8
pads (8):
  rect 2.3x2.3 hole 1.3: 1(-6.25,-2.5) 1(6.25,-2.5)
  round 2.1 hole 1.05: 1(-3.25,-2.25) 1(3.25,-2.25) 2(-3.25,2.25) 2(3.25,2.25)
  round 2.3 hole 1.3: 2(-6.25,2.5) 2(6.25,2.5)
Top Overlay:
  circle w0.2: c-7.75,-2.5 r0.1
  circle w0.254: c0,0 r1.581
  lines w0.127: -6,-3.788 -6,-6 6,-6 6,-3.788 ; -6,-1.212 -6,1.212 ; -6,3.788 -6,6 6,6 6,3.788 ; 6,-1.212 6,1.212
  lines w0.254: -3,-3 -3,3 3,3 3,-3 -3,-3
Mechanical 13:
  lines w0.127: -6,-6 -6,6 6,6 6,-6 -6,-6

## S_THT_TasterWagner [mm] "LB-2024-04-17"
pads (7):
  round 2.15 hole 1.15: 1(-2.54,1.73) 1(2.54,1.73) 2(0,4.27)
  round 1.75 hole 0.75: 3(1.27,-3.35)
  rect 1.75x1.75 hole 0.75: 4(-1.27,-3.35)
  round 0.1 hole 1.2 slot 2.5 at 90 deg: H1(-4.8,-4.3) H2(4.9,-4.4)
Top Overlay:
  lines w0.254: -5,-4.77 -2.54,-4.77 -2.54,-9.27 1.065,-9.27 2.54,-9.27 2.54,-4.77 5,-4.77 5,5.73 -5,5.73 -5,-4.77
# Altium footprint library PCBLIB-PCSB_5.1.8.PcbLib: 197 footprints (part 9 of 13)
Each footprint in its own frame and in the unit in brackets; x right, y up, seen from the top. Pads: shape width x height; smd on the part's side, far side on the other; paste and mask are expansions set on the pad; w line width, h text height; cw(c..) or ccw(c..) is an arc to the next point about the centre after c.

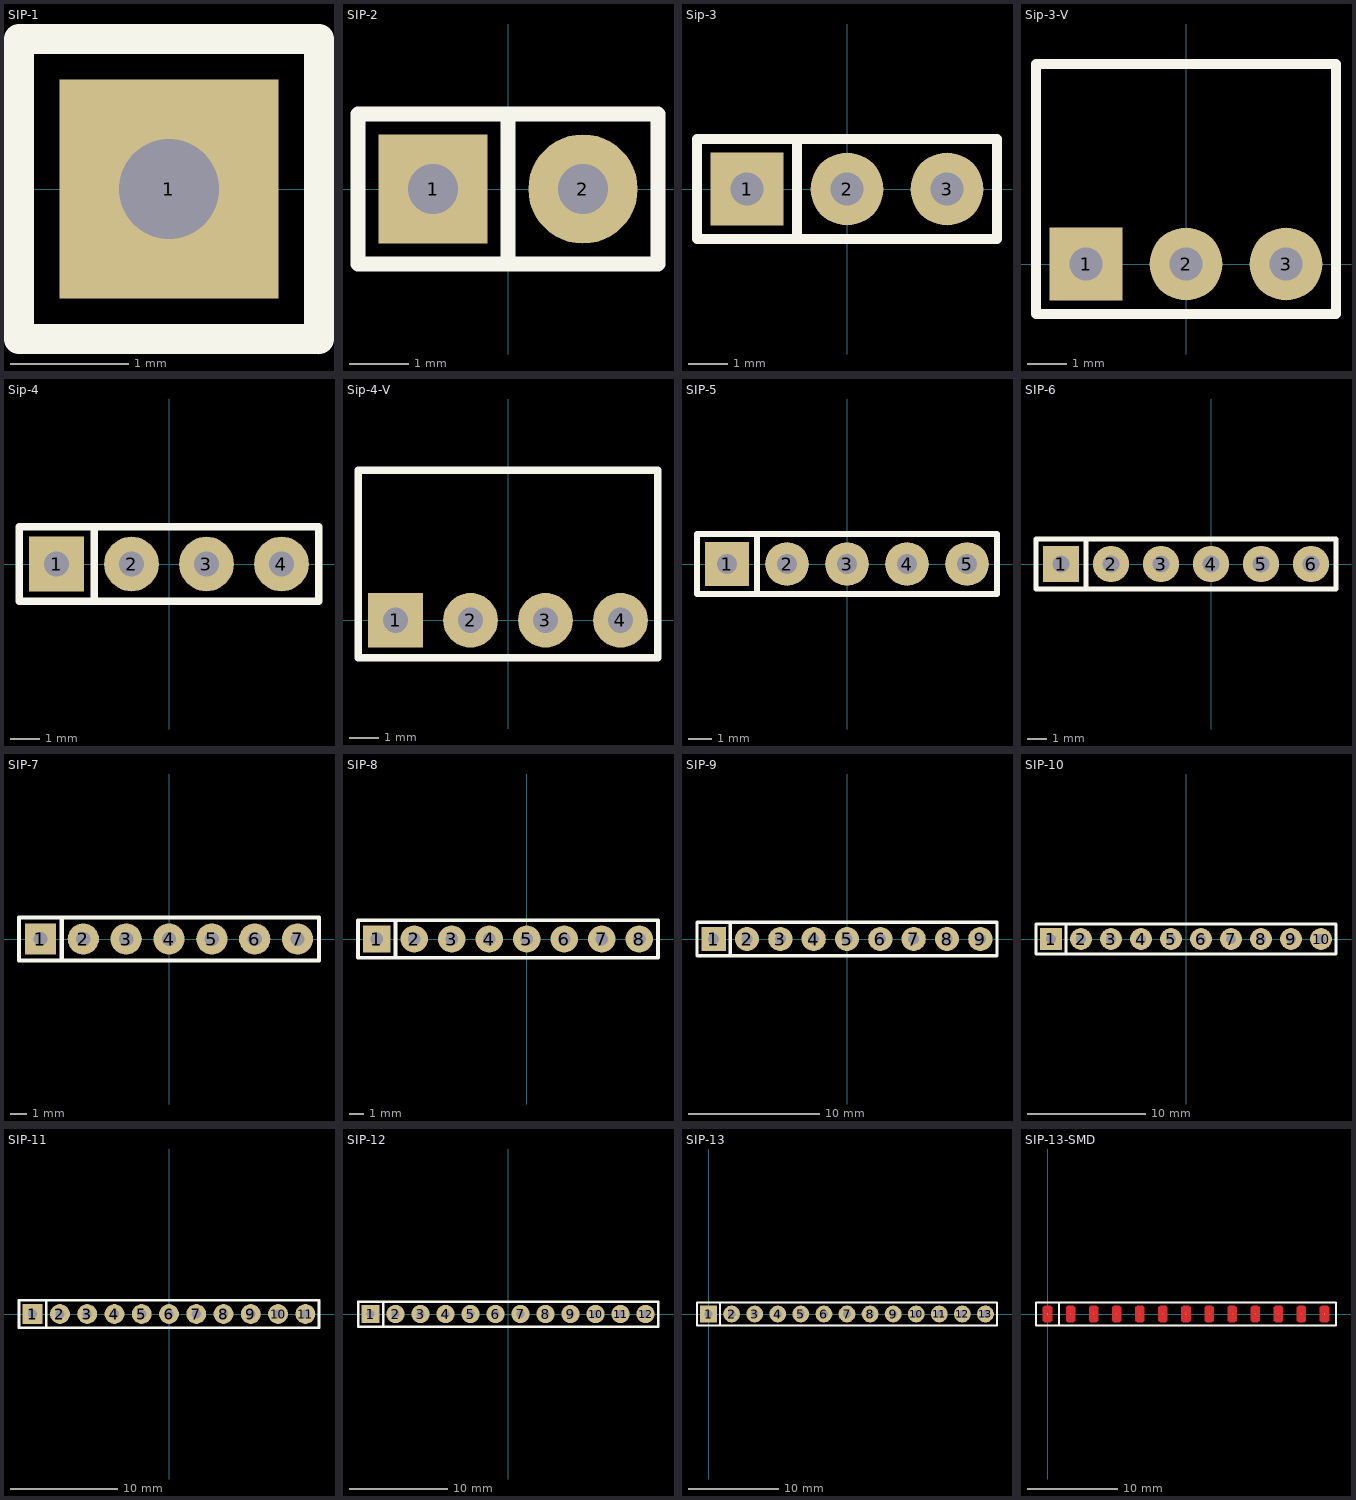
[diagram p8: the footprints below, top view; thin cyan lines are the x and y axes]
## SIP-1 [mm] "LB-2024-04-17"
pads (1):
  rect 1.85x1.85 hole 0.85: 1(-1.27,0)
Top Overlay:
  lines w0.254: -2.54,-1.27 0,-1.27 0,1.27 -2.54,1.27 -2.54,-1.27

## SIP-2 [mm] "LB-2024-04-17"
pads (2):
  rect 1.85x1.85 hole 0.85: 1(-1.27,0)
  round 1.85 hole 0.85: 2(1.27,0)
Top Overlay:
  lines w0.254: 0,-1.27 0,1.27 ; -2.54,-1.27 2.54,-1.27 2.54,1.27 -2.54,1.27 -2.54,-1.27

## Sip-3 [mm] "LB-2024-04-17"
pads (3):
  rect 1.85x1.85 hole 0.85: 1(-2.54,0)
  round 1.85 hole 0.85: 2(0,0) 3(2.54,0)
Top Overlay:
  lines w0.254: -1.27,-1.27 -1.27,1.27 ; -3.81,-1.27 3.81,-1.27 3.81,1.27 -3.81,1.27 -3.81,-1.27

## Sip-3-V [mm] "LB-2024-04-17"
pads (3):
  rect 1.85x1.85 hole 0.85: 1(-2.54,0)
  round 1.85 hole 0.85: 2(0,0) 3(2.54,0)
Top Overlay:
  lines w0.254: -3.81,-1.27 -3.81,5.08 3.81,5.08 3.81,-1.27 -3.81,-1.27

## Sip-4 [mm] "LB-2024-04-17"
pads (4):
  rect 1.85x1.85 hole 0.85: 1(-3.81,0)
  round 1.85 hole 0.85: 2(-1.27,0) 3(1.27,0) 4(3.81,0)
Top Overlay:
  lines w0.254: -2.54,-1.27 -2.54,1.27 ; -5.08,-1.27 -5.08,1.27 5.08,1.27 5.08,-1.27 -5.08,-1.27

## Sip-4-V [mm] "LB-2024-04-17"
pads (4):
  rect 1.85x1.85 hole 0.85: 1(-3.81,0)
  round 1.85 hole 0.85: 2(-1.27,0) 3(1.27,0) 4(3.81,0)
Top Overlay:
  lines w0.254: -5.08,-1.27 -5.08,5.08 5.08,5.08 5.08,-1.27 -5.08,-1.27

## SIP-5 [mm] "LB-2024-04-17"
pads (5):
  rect 1.85x1.85 hole 0.85: 1(-5.08,0)
  round 1.85 hole 0.85: 2(-2.54,0) 3(0,0) 4(2.54,0) 5(5.08,0)
Top Overlay:
  lines w0.254: -3.81,-1.27 -3.81,1.27 ; -6.35,-1.27 -6.35,1.27 6.35,1.27 6.35,-1.27 -6.35,-1.27

## SIP-6 [mm] "LB-2024-04-17"
pads (6):
  rect 1.85x1.85 hole 0.85: 1(-7.62,0)
  round 1.85 hole 0.85: 2(-5.08,0) 3(-2.54,0) 4(0,0) 5(2.54,0) 6(5.08,0)
Top Overlay:
  lines w0.254: -6.35,-1.27 -6.35,1.27 ; -8.89,-1.27 -8.89,1.27 6.35,1.27 6.35,-1.27 -8.89,-1.27

## SIP-7 [mm] "LB-2024-04-17"
pads (7):
  rect 1.85x1.85 hole 0.85: 1(-7.62,0)
  round 1.85 hole 0.85: 2(-5.08,0) 3(-2.54,0) 4(0,0) 5(2.54,0) 6(5.08,0) 7(7.62,0)
Top Overlay:
  lines w0.254: -6.35,-1.27 -6.35,1.27 ; -8.89,-1.27 8.89,-1.27 8.89,1.27 -8.89,1.27 -8.89,-1.27

## SIP-8 [mm] "LB-2024-04-17"
pads (8):
  rect 1.85x1.85 hole 0.85: 1(-10.16,0)
  round 1.85 hole 0.85: 2(-7.62,0) 3(-5.08,0) 4(-2.54,0) 5(0,0) 6(2.54,0) 7(5.08,0) 8(7.62,0)
Top Overlay:
  lines w0.254: -8.89,-1.27 -8.89,1.27 ; -11.43,-1.27 8.89,-1.27 8.89,1.27 -11.43,1.27 -11.43,-1.27

## SIP-9 [mm] "LB-2024-04-17"
pads (9):
  rect 1.85x1.85 hole 0.85: 1(-10.16,0)
  round 1.85 hole 0.85: 2(-7.62,0) 3(-5.08,0) 4(-2.54,0) 5(0,0) 6(2.54,0) 7(5.08,0) 8(7.62,0) 9(10.16,0)
Top Overlay:
  lines w0.254: -8.89,-1.27 -8.89,1.27 ; -11.43,-1.27 11.43,-1.27 11.43,1.27 -11.43,1.27 -11.43,-1.27

## SIP-10 [mm] "LB-2024-04-17"
pads (10):
  rect 1.85x1.85 hole 0.85: 1(-11.43,0)
  round 1.85 hole 0.85: 2(-8.89,0) 3(-6.35,0) 4(-3.81,0) 5(-1.27,0) 6(1.27,0) 7(3.81,0) 8(6.35,0) 9(8.89,0) 10(11.43,0)
Top Overlay:
  lines w0.254: -10.16,-1.27 -10.16,1.27 ; -12.7,-1.27 12.7,-1.27 12.7,1.27 -12.7,1.27 -12.7,-1.27

## SIP-11 [mm] "LB-2024-04-17"
pads (11):
  rect 1.85x1.85 hole 0.85: 1(-12.7,0)
  round 1.85 hole 0.85: 2(-10.16,0) 3(-7.62,0) 4(-5.08,0) 5(-2.54,0) 6(0,0) 7(2.54,0) 8(5.08,0) 9(7.62,0) 10(10.16,0) 11(12.7,0)
Top Overlay:
  lines w0.254: -11.43,-1.27 -11.43,1.27 ; -13.97,-1.27 -13.97,1.27 13.97,1.27 13.97,-1.27 -13.97,-1.27

## SIP-12 [mm] "LB-2024-04-17"
pads (12):
  rect 1.85x1.85 hole 0.85: 1(-13.97,0)
  round 1.85 hole 0.85: 2(-11.43,0) 3(-8.89,0) 4(-6.35,0) 5(-3.81,0) 6(-1.27,0) 7(1.27,0) 8(3.81,0) 9(6.35,0) 10(8.89,0) 11(11.43,0) 12(13.97,0)
Top Overlay:
  lines w0.254: -12.7,-1.27 -12.7,1.27 ; -15.24,-1.27 15.24,-1.27 15.24,1.27 -15.24,1.27 -15.24,-1.27

## SIP-13 [mm] "LB-2024-04-17"
pads (13):
  rect 1.85x1.85 hole 0.85: 1(0,0)
  round 1.85 hole 0.85: 2(2.54,0) 3(5.08,0) 4(7.62,0) 5(10.16,0) 6(12.7,0) 7(15.24,0) 8(17.78,0) 9(20.32,0) 10(22.86,0) 11(25.4,0) 12(27.94,0) 13(30.48,0)
Top Overlay:
  lines w0.254: 1.27,-1.27 1.27,1.27 ; -1.27,-1.27 -1.27,1.27 31.75,1.27 31.75,-1.27 -1.27,-1.27

## SIP-13-SMD [mil] "LB-2024-04-17"
pads (13):
  round 1 smd: 1(0,0) 2(100,0) 3(200,0) 4(300,0) 5(400,0) 6(500,0) 7(600,0) 8(700,0) 9(800,0) 10(900,0) 11(1000,0) 12(1100,0) 13(1200,0)
Top Layer:
  region: 680.31,-28.54 688.19,-36.42 711.81,-36.42 719.69,-28.54 719.69,28.54 711.81,36.42 688.19,36.42 680.31,28.54
  region: 580.31,-28.54 588.19,-36.42 611.81,-36.42 619.69,-28.54 619.69,28.54 611.81,36.42 588.19,36.42 580.31,28.54
  region: 480.31,-28.54 488.19,-36.42 511.81,-36.42 519.69,-28.54 519.69,28.54 511.81,36.42 488.19,36.42 480.31,28.54
  region: 380.31,-28.54 388.19,-36.42 411.81,-36.42 419.69,-28.54 419.69,28.54 411.81,36.42 388.19,36.42 380.31,28.54
  region: -19.69,-28.54 -11.81,-36.42 11.81,-36.42 19.69,-28.54 19.69,28.54 11.81,36.42 -11.81,36.42 -19.69,28.54
  region: 80.31,-28.54 88.19,-36.42 111.81,-36.42 119.69,-28.54 119.69,28.54 111.81,36.42 88.19,36.42 80.31,28.54
  region: 180.31,-28.54 188.19,-36.42 211.81,-36.42 219.69,-28.54 219.69,28.54 211.81,36.42 188.19,36.42 180.31,28.54
  region: 280.31,-28.54 288.19,-36.42 311.81,-36.42 319.69,-28.54 319.69,28.54 311.81,36.42 288.19,36.42 280.31,28.54
  region: 780.31,-28.54 788.19,-36.42 811.81,-36.42 819.69,-28.54 819.69,28.54 811.81,36.42 788.19,36.42 780.31,28.54
  region: 880.31,-28.54 888.19,-36.42 911.81,-36.42 919.69,-28.54 919.69,28.54 911.81,36.42 888.19,36.42 880.31,28.54
  region: 980.31,-28.54 988.19,-36.42 1011.81,-36.42 1019.69,-28.54 1019.69,28.54 1011.81,36.42 988.19,36.42 980.31,28.54
  region: 1080.31,-28.54 1088.19,-36.42 1111.81,-36.42 1119.69,-28.54 1119.69,28.54 1111.81,36.42 1088.19,36.42 1080.31,28.54
  region: 1180.31,-28.54 1188.19,-36.42 1211.81,-36.42 1219.69,-28.54 1219.69,28.54 1211.81,36.42 1188.19,36.42 1180.31,28.54
Top Overlay:
  lines w10: 50,-50 50,50 ; -50,-50 -50,50 1250,50 1250,-50 -50,-50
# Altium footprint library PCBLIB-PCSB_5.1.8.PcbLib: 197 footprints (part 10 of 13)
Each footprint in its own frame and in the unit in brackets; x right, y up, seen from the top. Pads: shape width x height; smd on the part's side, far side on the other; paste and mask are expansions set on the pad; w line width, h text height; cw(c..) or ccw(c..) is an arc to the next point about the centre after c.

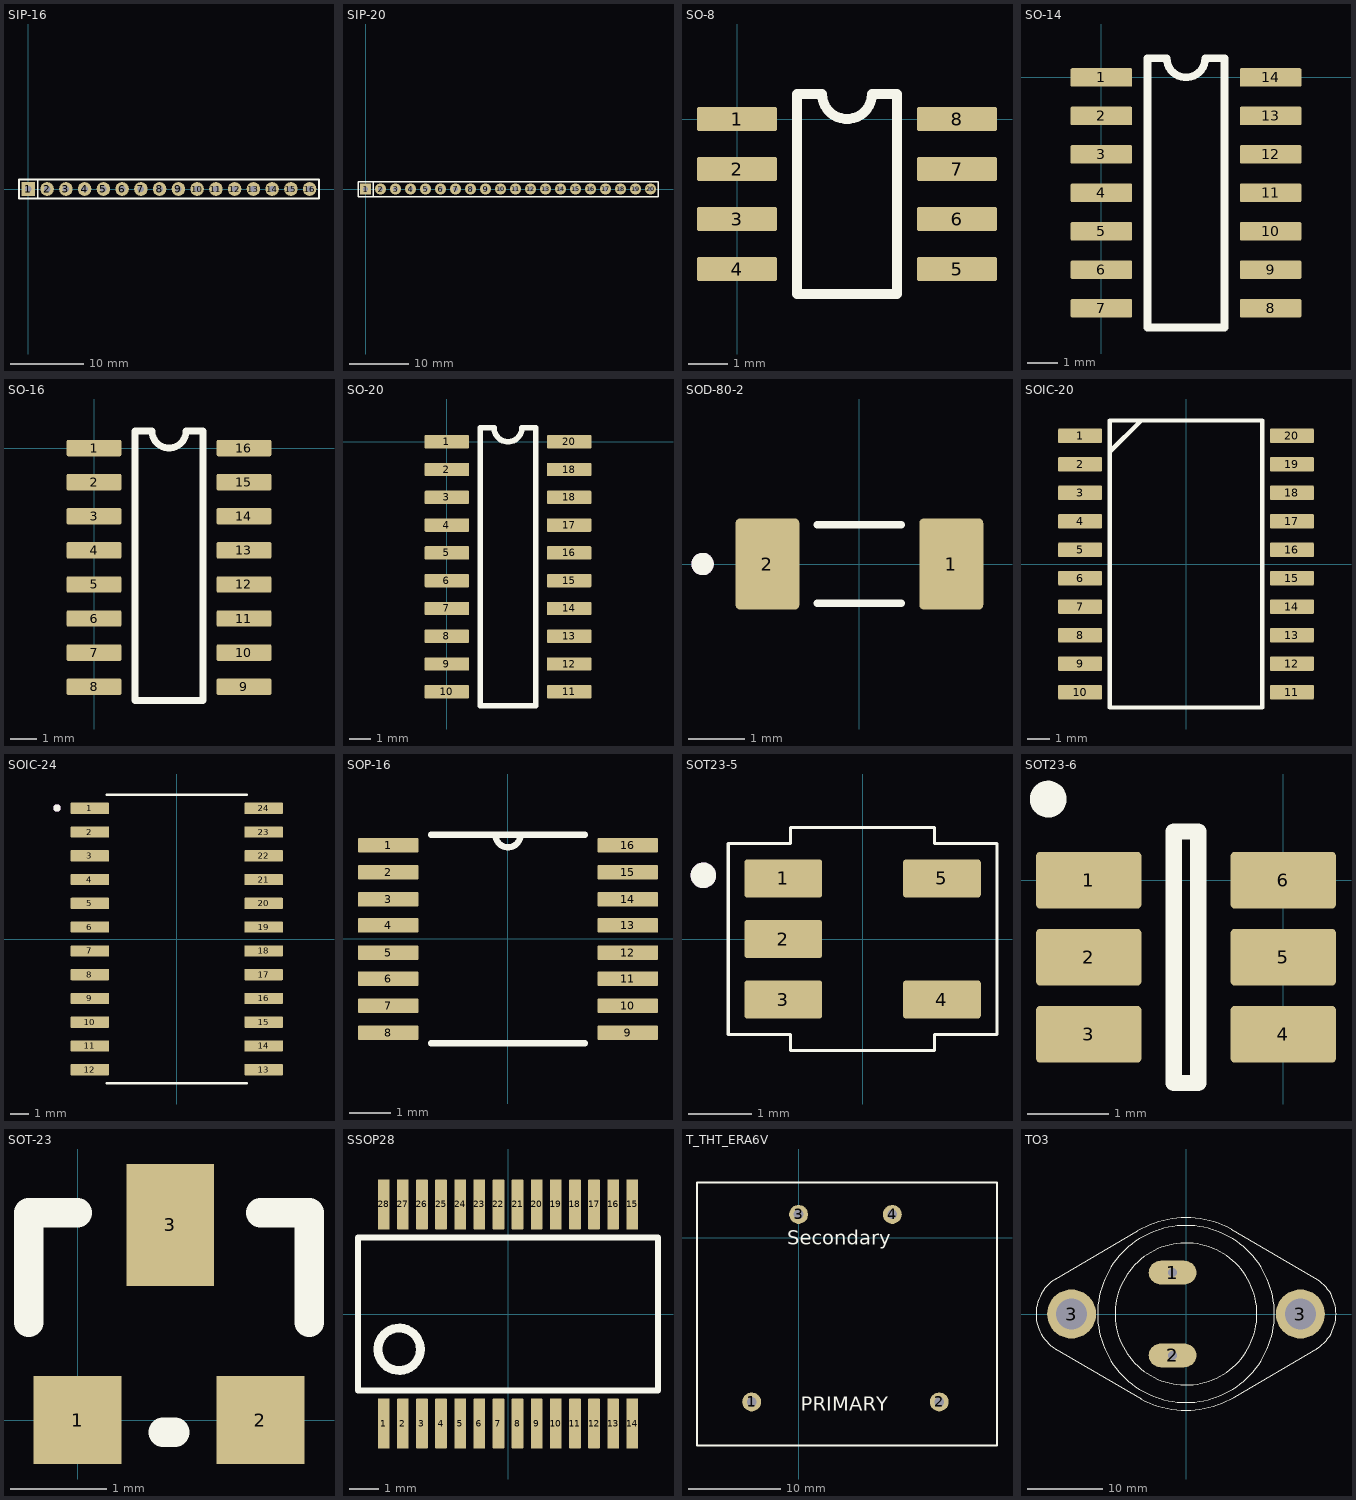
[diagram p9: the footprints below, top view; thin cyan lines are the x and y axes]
## SIP-16 [mm] "LB-2024-04-17"
pads (16):
  rect 1.85x1.85 hole 0.85: 1(0,0)
  round 1.85 hole 0.85: 2(2.54,0) 3(5.08,0) 4(7.62,0) 5(10.16,0) 6(12.7,0) 7(15.24,0) 8(17.78,0) 9(20.32,0) 10(22.86,0) 11(25.4,0) 12(27.94,0) 13(30.48,0) 14(33.02,0) 15(35.56,0) 16(38.1,0)
Top Overlay:
  lines w0.254: 1.27,-1.27 1.27,1.27 ; -1.27,-1.27 39.37,-1.27 39.37,1.27 -1.27,1.27 -1.27,-1.27

## SIP-20 [mm] "LB-2024-04-17"
pads (20):
  rect 1.85x1.85 hole 0.85: 1(0,0)
  round 1.85 hole 0.85: 2(2.54,0) 3(5.08,0) 4(7.62,0) 5(10.16,0) 6(12.7,0) 7(15.24,0) 8(17.78,0) 9(20.32,0) 10(22.86,0) 11(25.4,0) 12(27.94,0) 13(30.48,0) 14(33.02,0) 15(35.56,0) 16(38.1,0) 17(40.64,0) 18(43.18,0) 19(45.72,0) 20(48.26,0)
Top Overlay:
  lines w0.254: 1.27,-1.27 1.27,1.27 ; -1.27,-1.27 49.53,-1.27 49.53,1.27 -1.27,1.27 -1.27,-1.27

## SO-8 [mil] "LB-2024-04-17"
pads (8):
  rrect15% 80x24 smd paste-0.79 mask+1.97: 1(0,0) 2(0,-50) 3(0,-100) 4(0,-150) 5(220,-150) 6(220,-100) 7(220,-50) 8(220,0)
Top Overlay:
  lines w10: 60,-175 60,25 85,25 ccw(c110,25) 135,25 160,25 160,-175 60,-175

## SO-14 [mil] "LB-2024-04-17"
pads (14):
  rrect15% 80x24 smd paste-0.79 mask+1.97: 1(0,0) 2(0,-50) 3(0,-100) 4(0,-150) 5(0,-200) 6(0,-250) 7(0,-300) 8(220,-300) 9(220,-250) 10(220,-200) 11(220,-150) 12(220,-100) 13(220,-50) 14(220,0)
Top Overlay:
  lines w10: 60,-325 160,-325 160,25 135,25 cw(c110,25) 85,25 60,25 60,-325

## SO-16 [mil] "LB-2024-04-17"
pads (16):
  rrect15% 80x24 smd paste-0.79 mask+1.97: 1(0,0) 2(0,-50) 3(0,-100) 4(0,-150) 5(0,-200) 6(0,-250) 7(0,-300) 8(0,-350) 9(220,-350) 10(220,-300) 11(220,-250) 12(220,-200) 13(220,-150) 14(220,-100) 15(220,-50) 16(220,0)
Top Overlay:
  lines w10: 60,-370 60,25 85,25 ccw(c110,25) 135,25 160,25 160,-370 60,-370

## SO-20 [mil] "LB-2024-04-17"
pads (20):
  rrect15% 80x24 smd paste-0.79 mask+1.97: 1(0,0) 2(0,-50) 3(0,-100) 4(0,-150) 5(0,-200) 6(0,-250) 7(0,-300) 8(0,-350) 9(0,-400) 10(0,-450) 11(220,-450) 12(220,-400) 13(220,-350) 14(220,-300) 15(220,-250) 16(220,-200) 17(220,-150) 18(220,-100) 18(220,-50) 20(220,0)
Top Overlay:
  lines w10: 60,-475 60,25 85,25 ccw(c110,25) 135,25 160,25 160,-475 60,-475

## SOD-80-2 [mm]
pads (2):
  rrect15% 1.14x1.63 smd paste-0.02 mask+0.05: 1(1.64,0) 2(-1.64,0)
Top Overlay:
  circle w0.2: c-2.795,0 r0.1
  lines w0.127: -0.75,-0.7 0.75,-0.7 ; -0.75,0.7 0.75,0.7
Mechanical 13:
  circle w0.2: c-2.795,0 r0.1
  lines w0.127: -1.7,-0.7 -1.7,0.7 ; 1.7,-0.7 1.7,0.7

## SOIC-20 [mm] "LB-2025-01-10"
pads (20):
  rrect15% 1.95x0.65 smd paste-0.02 mask+0.05: 1(-4.725,5.715) 2(-4.725,4.445) 3(-4.725,3.175) 4(-4.725,1.905) 5(-4.725,0.635) 6(-4.725,-0.635) 7(-4.725,-1.905) 8(-4.725,-3.175) 9(-4.725,-4.445) 10(-4.725,-5.715) 11(4.725,-5.715) 12(4.725,-4.445) 13(4.725,-3.175) 14(4.725,-1.905) 15(4.725,-0.635) 16(4.725,0.635) 17(4.725,1.905) 18(4.725,3.175) 19(4.725,4.445) 20(4.725,5.715)
Top Overlay:
  lines w0.2: -3.4,5 -2,6.4 ; -3.4,-6.4 -3.4,6.4 3.4,6.4 3.4,-6.4 -3.4,-6.4

## SOIC-24 [mm]
height 2.65
pads (24):
  rrect15% 2.06x0.6 smd paste-0.02 mask+0.05: 1(-4.64,6.985) 2(-4.64,5.715) 3(-4.64,4.445) 4(-4.64,3.175) 5(-4.64,1.905) 6(-4.64,0.635) 7(-4.64,-0.635) 8(-4.64,-1.905) 9(-4.64,-3.175) 10(-4.64,-4.445) 11(-4.64,-5.715) 12(-4.64,-6.985) 13(4.64,-6.985) 14(4.64,-5.715) 15(4.64,-4.445) 16(4.64,-3.175) 17(4.64,-1.905) 18(4.64,-0.635) 19(4.64,0.635) 20(4.64,1.905) 21(4.64,3.175) 22(4.64,4.445) 23(4.64,5.715) 24(4.64,6.985)
Top Overlay:
  circle w0.2: c-6.4,7 r0.1
  lines w0.127: -3.75,-7.7 3.75,-7.7 ; -3.75,7.7 3.75,7.7
Mechanical 13:
  circle w0.2: c-6.4,7 r0.1

## SOP-16 [mil] "LB-2024-04-17"
pads (16):
  rrect15% 58x14 smd paste-0.79 mask+1.97: 1(-115,90) 2(-115,64) 3(-115,38) 4(-115,13) 5(-115,-13) 6(-115,-38) 7(-115,-64) 8(-115,-90) 9(115,-90) 10(115,-64) 11(115,-38) 12(115,-13) 13(115,13) 14(115,38) 15(115,64) 16(115,90)
Top Overlay:
  lines w6: -74,-100 74,-100 ; -74,100 -12,100 ; 74,100 12,100 ; -12,100 ccw(c0,100) 12,100 ; -12,100 12,100
Mechanical 13:
  lines w0: -12,100 ccw(c0,100) 12,100

## SOT23-5 [mm]
pads (5):
  rrect15% 1.22x0.6 smd paste-0.02 mask+0.05: 1(-1.245,0.95) 2(-1.245,0) 3(-1.245,-0.95) 4(1.245,-0.95) 5(1.245,0.95)
Top Overlay:
  circle w0.2: c-2.5,1 r0.1
  lines w0.05: -2.11,-1.5 -2.11,1.5 -1.13,1.5 -1.13,1.75 1.13,1.75 1.13,1.5 2.11,1.5 2.11,-1.5 1.13,-1.5 1.13,-1.75 -1.13,-1.75 -1.13,-1.5 -2.11,-1.5
Mechanical 13:
  circle w0.2: c-2.5,1 r0.1

## SOT23-6 [mm] "LB-2024-04-25"
height 1.45
pads (6):
  rrect15% 1.3x0.7 smd paste-0.02 mask+0.05: 1(-2.4,0) 2(-2.4,-0.95) 3(-2.4,-1.9) 4(0,-1.9) 5(0,-0.95) 6(0,0)
Top Overlay:
  circle w0.254: c-2.9,1 r0.1
  lines w0.2: -1.35,-2.5 -1.05,-2.5 -1.05,0.6 -1.35,0.6 -1.35,-2.5

## SOT-23 [mil]
pads (3):
  rect 36x36 smd: 1(0,0) 2(75,0)
  rect 36x50 smd: 3(38,80)
Top Overlay:
  lines w12: -20,40 -20,85 0,85 ; 35,-5 40,-5 ; 75,85 95,85 95,40

## SSOP28 [mm] "LB-2024-09-01"
pads (28):
  rrect15% 0.4x1.7 smd paste-0.02 mask+0.05: 1(-4.225,-3.725) 2(-3.575,-3.725) 3(-2.925,-3.725) 4(-2.275,-3.725) 5(-1.625,-3.725) 6(-0.975,-3.725) 7(-0.325,-3.725) 8(0.325,-3.725) 9(0.975,-3.725) 10(1.625,-3.725) 11(2.275,-3.725) 12(2.925,-3.725) 13(3.575,-3.725) 14(4.225,-3.725) 15(4.225,3.725) 16(3.575,3.725) 17(2.925,3.725) 18(2.275,3.725) 19(1.625,3.725) 20(0.975,3.725) 21(0.325,3.725) 22(-0.325,3.725) 23(-0.975,3.725) 24(-1.625,3.725) 25(-2.275,3.725) 26(-2.925,3.725) 27(-3.575,3.725) 28(-4.225,3.725)
Top Overlay:
  circle w0.3: c-3.7,-1.2 r0.721
  lines w0.203: -5.1,-2.6 -5.1,2.6 5.1,2.6 5.1,-2.6 -5.1,-2.6

## T_THT_ERA6V [mm] "LB-2024-04-17"
pads (4):
  round 2.05 hole 1.05: 1(-5.08,-17.78) 2(15.24,-17.78) 3(0,2.54) 4(10.16,2.54)
Top Overlay:
  lines w0.254: -11,-22.5 21.5,-22.5 21.5,6 -11,6 -11,-22.5
  text "PRIMARY" at 0.254,-18.746 h1.52
  text "Secondary" at -1.246,-0.738 h1.52

## TO3 [mil] "LB-2024-04-17"
pads (4):
  oval 248x124 hole 47.05: 1(-70,215) 2(-70,-215)
  round 255 hole 162: 3(-595,0) 3(595,0)
Top Overlay:
  circle w6: c0,0 r369
  circle w2: c0,0 r460
  lines w6: -680,180 -250,433 cw(c0,0) 0,500 cw(c0,0) 234.74,441.47 ; -679,-181 -234,-442 ; -676.7,-182.58 cw(c-567,0) -780,0 cw(c-567,0) -673.5,184.46 ; -234.74,-441.47 ccw(c0,0) 0,-500 ccw(c0,0) 250,-433.01 ; 235,441 684,178 ; 251,-433 684,-178 ; 683.01,-178.64 ccw(c567,0) 780,0 ccw(c567,0) 683.01,178.64
Mechanical 13:
  circle w6: c595,0 r85
  circle w6: c-595,0 r85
